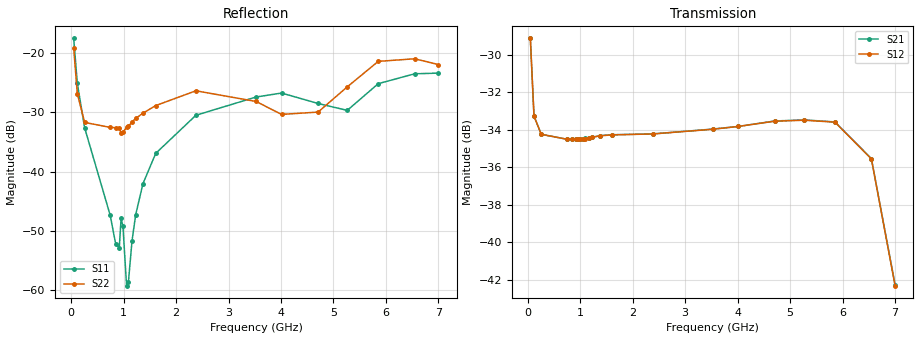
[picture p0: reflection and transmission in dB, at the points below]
! Integrated Device Technology
! Corporate Headquarters
! 6024 Silver Creek Valley Road
! San Jose, CA 95138  USA
! Phone:  1-408-284-8200
! Toll Free:  1-800-223-1366
! Webpage:  http://www.idt.com/
! Timing and RF Division
! 515 Groton Road, Suite 102
! Westford, MA 01886-6024
! Device:  F2258
! Description: Voltage Variable RF Attenuator
! Frequency:  50.0 -  6000.00 MHz
! Package:  3x3 mm Thin QFN Plastic Package: 16 pin
! Ports:  2 RF, 2 DC
!  Pin  1  = NC
!  Pin  2  = NC
!  Pin  3  = RF2  = Port 2
!  Pin  4  = GND
!  Pin  5  = Vdd
!  Pin  6  = NC
!  Pin  7  = VCTRL
!  Pin  8  = NC
!  Pin  9  = GND
!  Pin 10  = RF1  = Port 1
!  Pin 11  = NC
!  Pin 12  = NC
!  Pin 13  = NC
!  Pin 14  = NC
!  Pin 15  = NC
!  Pin 16  = NC
! Vcntrl:  1.900 Volts
! Vdd:  +3.300 Volts
! Current:  1.156 mA
! Data:  The device was measured on a the F2258 evaluation board which has
!  individual transmission lines to the RF pins.  Data was collected
!  using a calibrated network analyzer.  The evaluation board was
!  de-embedded using a TRL calibration technique.
!  The reference plane is the edge of the package pin.
! Misc:  SN 10
!  Action Tracker AT0285
! Date Measured:  2014-12-10
! Date:  2016-01-13  MJV
! Note:
!  Integrated Device Technology supplies this data as a sample of measured
!  data at the package pin for this product.  Your particular data for this
!  product may vary.
!  Data was taken at 25 degrees C.
!  Integrated Device Technology reserves the right to change this data at anytime.
!Freq_(GHz)  S11M_(dB)  S11P_(deg)  S21M_(dB)  S21P_(deg)  S12M_(dB)  S12P_(deg)  S22M_(dB)  S22P_(deg)
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# GHz S dB R 50
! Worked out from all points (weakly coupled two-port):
!   201 points, 50 MHz to 7 GHz, reference 50 ohm
!   highest |S21| = -29.13 dB at 50 MHz (marker M1); lowest = -42.2 dB at 7 GHz (marker M2)
!   lowest |S11| = -59.3 dB at 1.058 GHz (marker M3), VSWR 1.00, Z = 49.9 + j0.0506 ohm
!   |S11| at or under -10 dB: start of sweep to end of sweep
!   |S22| runs from -33.5 to -19.2 dB; largest |S21 - S12| = 0.00011
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0.05  -17.55 -110.8  -29.13 -64.6  -29.13 -64.6  -19.19 -103.7
0.1195  -25.12 -106.6  -33.27 -34.4  -33.27 -34.4  -26.89 -76.1
0.2585  -32.62 -111.3  -34.24 -17.7  -34.24 -17.8  -31.72 -42.9
0.745  -47.35 -141.2  -34.50 -9.3  -34.50 -9.3  -32.56 -1.7
0.84925  -52.16 -172.4  -34.51 -9.0  -34.51 -9.0  -32.62 1.1
0.91875  -52.83 149.0  -34.50 -8.9  -34.51 -8.9  -32.64 1.3
0.9535  -47.90 -161.0  -34.51 -8.8  -34.51 -8.8  -33.52 7.8
0.98825  -49.17 -173.0  -34.49 -8.8  -34.50 -8.8  -33.39 6.5
1.05775  -59.25 152.3  -34.48 -8.7  -34.49 -8.7  -32.56 7.3
1.0925  -58.65 113.1  -34.46 -8.7  -34.47 -8.7  -32.39 7.5
1.162  -51.67 65.8  -34.43 -8.7  -34.44 -8.7  -31.64 7.5
1.2315  -47.28 43.7  -34.40 -8.9  -34.40 -8.9  -31.06 7.3
1.3705  -42.04 35.7  -34.31 -9.4  -34.32 -9.4  -30.15 8.2
1.61375  -36.94 32.1  -34.26 -10.8  -34.27 -10.8  -28.88 7.5
2.37825  -30.52 47.7  -34.22 -14.9  -34.22 -14.9  -26.39 10.5
3.525  -27.44 91.4  -33.96 -22.0  -33.97 -22.0  -28.19 32.2
4.0115  -26.77 104.4  -33.82 -25.8  -33.82 -25.7  -30.37 41.4
4.7065  -28.53 95.5  -33.53 -31.6  -33.54 -31.5  -29.98 20.8
5.2625  -29.69 54.0  -33.47 -37.7  -33.49 -37.6  -25.73 -7.7
5.85325  -25.19 29.7  -33.58 -47.9  -33.59 -47.9  -21.43 -19.7
6.54825  -23.52 45.0  -35.53 -67.3  -35.55 -67.2  -20.99 -51.1
7  -23.41 84.4  -42.25 -63.6  -42.30 -63.2  -21.97 -126.0
